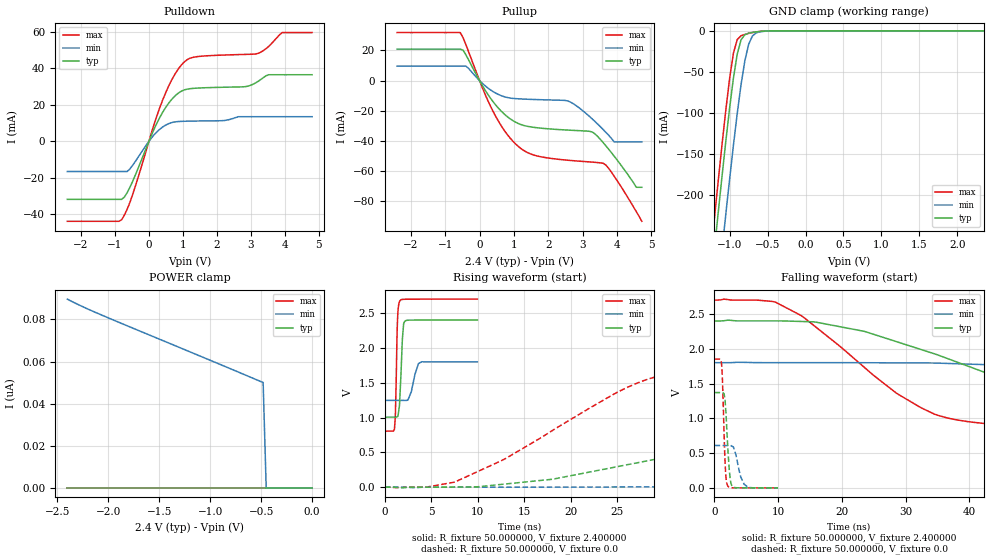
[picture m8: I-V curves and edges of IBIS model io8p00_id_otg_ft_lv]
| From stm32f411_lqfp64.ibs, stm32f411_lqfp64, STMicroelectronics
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|   Model io8p00_id_otg_ft_lv
[Model]  io8p00_id_otg_ft_lv
Model_type I/O
Polarity   Non-Inverting
Enable   Active-Low
Vinl =   0.720000V
Vinh =   1.680000V
Vmeas =  1.200000V
Cref =   50.000000pF
Rref =   100.000000M
Vref =   0.0V
C_comp   2.229800pF   2.169700pF   2.325100pF
[Temperature Range]   25.000000   0.125000k   -40.000000
[Pullup Reference]   2.400000V   1.800000V   2.700000V
[Pulldown Reference]   0.0V   0.0V   0.0V
[POWER Clamp Reference]   2.400000V   1.800000V   2.700000V
[GND Clamp Reference]   0.0V   0.0V   0.0V
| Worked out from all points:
|   slope of the pulldown table from 0 to 0.36 V, typ, clamps not added: 25 ohm
|   slope of the pullup table from 0 to 0.36 V, typ, clamps not added: 27.7 ohm
|   GND clamp passes 1 mA (typ) near -0.62 V on its own axis
|   rising waveform, R_fixture 50.000000, V_fixture 2.400000: 20-80 % time 272ps typ, 604ps min, 183ps max; typ from 1.01 V to 2.4 V
|   rising waveform, R_fixture 50.000000, V_fixture 0.0: 20-80 % time 32.8ns typ, 82.1ns min, 14.6ns max; typ from 0 V to 1.37 V
|   falling waveform, R_fixture 50.000000, V_fixture 2.400000: 20-80 % time 29.4ns typ, 74.4ns min, 16ns max; typ from 2.4 V to 1.01 V
|   falling waveform, R_fixture 50.000000, V_fixture 0.0: 20-80 % time 523ps typ, 978ps min, 386ps max; typ from 1.37 V to 0 V
[Pulldown]
|Voltage   I(typ)   I(min)   I(max)
-2.4V     -31.73mA   -16.51mA   -43.74mA
-800mV    -31.73mA   -16.51mA   -42.87mA
-480mV    -21.98mA   -13.17mA   -29.21mA
80mV      3.63mA     1.966mA    5.014mA
480mV     18.16mA    8.738mA    26.02mA
800mV     25.38mA    10.72mA    37.77mA
1.12V     28.53mA    11.02mA    44.6mA
2.8V      29.84mA    13.49mA    47.53mA
3.2V      32.65mA    13.49mA    48.05mA
3.52V     36.43mA    13.49mA    51.84mA
3.92V     36.43mA    13.49mA    59.49mA
4.8V      36.43mA    13.49mA    59.49mA
[Pullup]
|Voltage   I(typ)   I(min)   I(max)
-2.4V     20.89mA    9.661mA    31.91mA
-560mV    20.89mA    9.661mA    31.91mA
-400mV    17.28mA    9.661mA    24.07mA
320mV     -11.75mA   -6.207mA   -17.08mA
960mV     -26.47mA   -11.82mA   -40.02mA
1.52V     -30.88mA   -12.51mA   -49.05mA
2.56V     -32.88mA   -13.48mA   -52.9mA
3.28V     -34.19mA   -25.52mA   -54.18mA
3.6V      -41.31mA   -32.62mA   -54.97mA
3.92V     -50.32mA   -40.8mA    -63.63mA
4.56V     -70.9mA    -40.8mA    -87.08mA
4.72V     -70.9mA    -40.8mA    -93.5mA
[GND_clamp]
|Voltage   I(typ)   I(min)   I(max)
-2.4V     -1.424A    -1.508A    -1.393A
-1.25V    -311.2mA   -401.9mA   -273.3mA
-1.2V     -265.4mA   -356.1mA   -227.2mA
-1.15V    -220.4mA   -310.8mA   -181.9mA
-1.1V     -176.3mA   -266.2mA   -137.9mA
-1.05V    -133.8mA   -222.5mA   -95.88mA
-950mV    -57.31mA   -138.9mA   -26.99mA
-900mV    -28.28mA   -100.4mA   -10.61mA
-850mV    -11.02mA   -65.55mA   -5.978mA
-750mV    -2.847mA   -16.51mA   -3.192mA
-600mV    -755.4uA   -1.17mA    -743.6uA
2.35V     0A         0A         0A
[POWER_clamp]
|Voltage   I(typ)   I(min)   I(max)
-2.4V     0A         89.62nA    0A
-2.04V    0A         81.58nA    0A
-480mV    0A         50.01nA    0A
-450mV    0A         0A         0A
0V        0A         0A         0A
[Ramp]
| variable   typ   min   max
dV/dt_r  0.82236/32.80452n   0.36279/85.12256n   1.11120/14.54537n
dV/dt_f  0.83736/29.38597n   0.32736/79.52214n   1.13726/16.03096n
R_load = 50.000000
[Rising Waveform]
R_fixture= 50.000000
V_fixture= 2.400000
V_fixture_min= 1.800000
V_fixture_max= 2.700000
|time   V(typ)   V(min)   V(max)
0s        1.006V     1.247V     804.6mV
1.041ns   1.006V     1.247V     831.5mV
1.141ns   1.006V     1.247V     1.042V
1.381ns   1.014V     1.247V     2.438V
1.642ns   1.336V     1.247V     2.678V
1.902ns   2.138V     1.247V     2.696V
2.162ns   2.384V     1.245V     2.698V
2.503ns   2.398V     1.255V     2.699V
3.824ns   2.4V       1.789V     2.7V
9.97ns    2.4V       1.8V       2.7V
[Rising Waveform]
R_fixture= 50.000000
V_fixture= 0.0
V_fixture_min= 0.0
V_fixture_max= 0.0
|time   V(typ)   V(min)   V(max)
0s        4.248nV    257.3nV    1.628nV
7.508ns   2.145mV    -50.61uV   72.84mV
18.02ns   113.7mV    452.1uV    811.6mV
28.53ns   385.5mV    4.796mV    1.56V
36.04ns   598.7mV    21.71mV    1.735V
44.54ns   844mV      45.9mV     1.8V
67.57ns   1.256V     133mV      1.844V
83.08ns   1.326V     209mV      1.848V
148.1ns   1.368V     490.1mV    1.852V
249.2ns   1.37V      609.1mV    1.852V
[Falling Waveform]
R_fixture= 50.000000
V_fixture= 2.400000
V_fixture_min= 1.800000
V_fixture_max= 2.700000
|time   V(typ)   V(min)   V(max)
0s        2.4V       1.8V       2.7V
9.51ns    2.4V       1.8V       2.673V
14.01ns   2.391V     1.8V       2.45V
23.52ns   2.25V      1.799V     1.733V
32.03ns   2.001V     1.796V     1.173V
43.54ns   1.625V     1.769V     914.1mV
63.06ns   1.209V     1.694V     840.6mV
87.59ns   1.071V     1.557V     817mV
124.1ns   1.024V     1.384V     807.4mV
249.2ns   1.006V     1.247V     804.6mV
[Falling Waveform]
R_fixture= 50.000000
V_fixture= 0.0
V_fixture_min= 0.0
V_fixture_max= 0.0
|time   V(typ)   V(min)   V(max)
0s        1.37V      609.1mV    1.852V
1.061ns   1.37V      609.1mV    1.819V
1.241ns   1.37V      609mV      1.572V
1.682ns   1.234V     608.8mV    324.7mV
1.842ns   1.005V     608.5mV    115.8mV
2.062ns   623.7mV    608.4mV    31.27mV
2.482ns   120mV      610.7mV    3.861mV
2.843ns   18.35mV    594.2mV    1.006mV
4.645ns   108.3uV    53.11mV    30.68uV
9.97ns    4.248nV    257.3nV    1.628nV
